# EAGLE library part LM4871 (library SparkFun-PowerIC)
3W audio amplifier

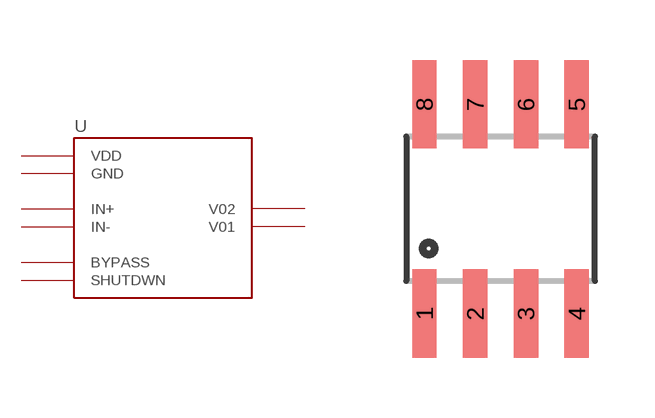
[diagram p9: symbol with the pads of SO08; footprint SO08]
Designator prefix -

## LM4871  [SO08]
1  SHUTDWN
2  BYPASS
3  IN+
4  IN-
5  V01
6  VDD
7  GND
8  V02

## Footprint SO08 (pad centres in mm)
Small Outline Package Fits JEDEC packages (narrow SOIC-8)
smd 0.61 x 2.21: 1 -1.905,-2.616; 2 -0.635,-2.616; 3 0.635,-2.616; 4 1.905,-2.616; 5 1.905,2.616; 6 0.635,2.616; 7 -0.635,2.616; 8 -1.905,2.616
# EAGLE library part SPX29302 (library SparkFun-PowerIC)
3A LDO regulator

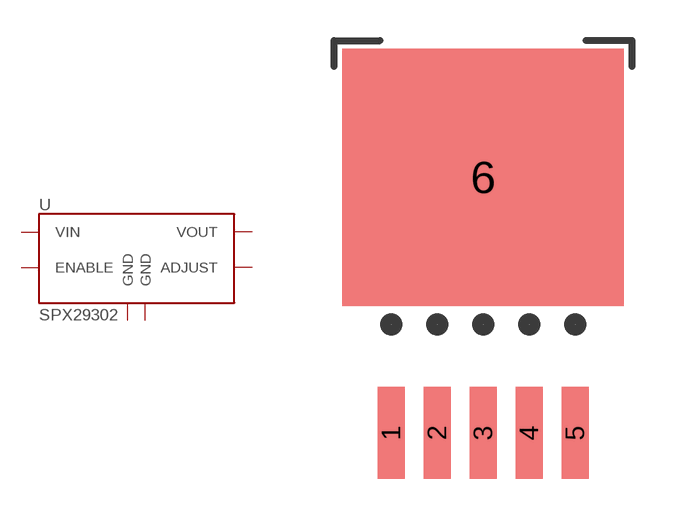
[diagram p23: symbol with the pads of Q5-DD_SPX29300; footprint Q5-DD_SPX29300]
Designator prefix U

## SPX29302 (PROD_ID: VREG-08337)  [Q5-DD_SPX29300]
1  ENABLE
2  VIN
3  GND
4  VOUT
5  ADJUST
6  GND

## Footprint Q5-DD_SPX29300 (pad centres in mm)
smd 1 x 3.4: 1 -3.4,-7.875; 2 -1.7,-7.875; 3 0,-7.875; 4 1.7,-7.875; 5 3.4,-7.875
smd 10.414 x 9.525: 6 0,1.595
